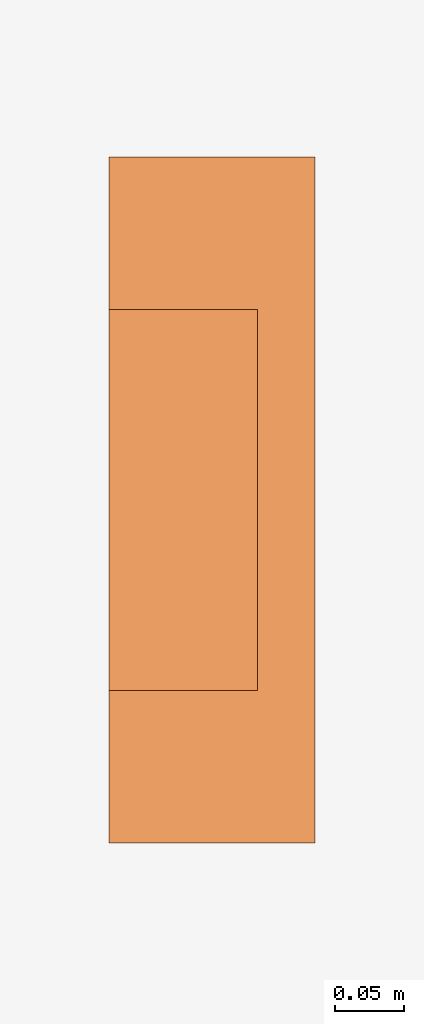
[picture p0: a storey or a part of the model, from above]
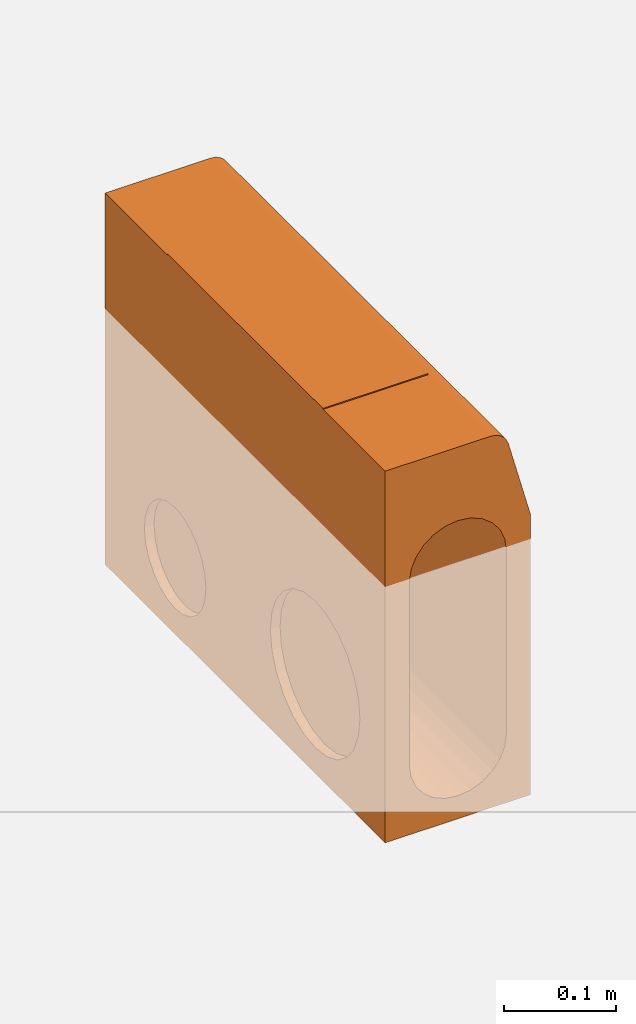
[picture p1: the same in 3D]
Properties of the parts of a building model (IFC2X3)

# File
Description: ViewDefinition [CoordinationView]
File name: 4233 - Access Unit - 500mm LG.ifc
Time: 2013-09-02T12:40:25
Written by: Autodesk Revit 2013
Made in: 20120221_2030(x64)

# IfcProject, Project Number
LongName: Project Name; Phase: Project Status

# IfcSite, Default
RefLatitude: 42, 21, 30, 344238; RefLongitude: -71, -3, -35, -194702; RefElevation: 0 mm

# IfcBuilding
Pset_BuildingCommon - NumberOfStoreys: 1
Other - Project Address: ## Street City, State Zip; Project Name: Project Name; Project Issue Date: Issue Date; Project Status: Project Status; Project Number: Project Number; Client Name: Owner

# IfcBuildingStorey, Level 1
LongName: Level 1; Elevation: 0 mm
Constraints - Elevation Base: 0; Elevation: 0 mm
Graphics - Line Pattern: Center; Symbol: M_Level Head - Circle: M_Level Head - Circle; Symbol at End 1 Default: no; Line Weight: 1; Symbol at End 2 Default: yes; Color: 0
Dimensions - Computation Height: 0 mm
Identity Data - Name: Level 1; Structural: no; Building Story: yes

# IfcBuildingElementProxy: 4233 - Access Unit - 500mm LG, Civil-Drainage-Channel-ACO-KerbDrain-HB405:4233 - Access Unit - 500mm LG:4233 - Access Unit - 500mm LG:312781
In: Level 1
Material: ACO Polymer Concrete., Iron, Cast
Constraints - Level: Level: Level 1; Moves With Nearby Elements: no
Dimensions - Volume: 15157016 mm3; Circular Void Depth: 2000 mm; Void Width: 150 mm; Void Length: 500 mm; Void Depth: -280 mm
Phasing - Phase Created: New Construction
Pset_BuildingElementProxyCommon - Reference: 4233 - Access Unit - 500mm LG
Construction - RH inlet/outlet end cap: no; HB405 - 500: no; RH drop kerb: no; HB405 500_blindunit: no; Closing end cap: no; HB405 - 1000: no; Centre Stone: no; Access Unit: yes; LH drop kerb: no; LH inlet/outlet end cap: no
Materials and Finishes - Connection Pipe Material Colour: N/A; End Cap Material: N/A; Access Cover/Frame Material: Ductile Iron; Channel Colour: Grey; Access Cover/Frame Finish: Water Based Paint Coating; Channel Material: Vienite® Synthetic Resin Concrete; End Cap Colour: N/A; Access Cover/Frame Colour: Black; Connection Pipe Material: N/A
Identity Data - Telephone: +44 (0)1462 816666; OmniClass Title: Rainwater Removal; Model: ACO KerbDrain HB405; Price: POA - contact ACO; OmniClass Number: 23.70.50.24; Installation guidelines: http://www.aco.co.uk/download.php?id=120; e-mail Technical: technical@aco.co.uk; Address: ACO Business Park, Hitchin Road, Shefford, Bedfordshire, United Kingdom SG17 5TE; Maintenance guidelines: http://www.aco.co.uk/download.php?id=120; Cost: 0; Assembly Description: Rain Water Drainage; Assembly Code: D2040; Manufacturer: ACO Technologies plc - ACO Water Management Division; URL: www.aco.co.uk; Product brochure: http://www.aco.co.uk/download.php?id=120; Model Description: Combined kerb and drainage system; Product Code: 4233; Type Comments: ACO KerbDrain HB405 half battered access unit 500mm long; Product Page URL: http://www.aco.co.uk/product_detail.php?id=3; e-mail Sales: customersupport@aco.co.uk; Fax: +44 (0)1462 815895
Data - Channel C.S.A: 0.03m²; ACO Hydraulic Design Software: http://www.acodesign.co.uk; Concrete Surround Volume - Load Class A 15 - D 400 - Grass or Asphalt Pavement: 0.16m³/m; Hydraulic Performance: http://www.aco.co.uk/download.php?id=120; Product Weight: 34.3 Kg; Load Class: A 15 - D 400; Drainage Slot Width: N/A; Product Dimensions: 500mm x 150mm x 405mm (LxWxH); Invert Depth: 380mm; Concrete Surround Volume - Load Class A 15 - D 400 - Concrete Pavement: 0.17m³/m; Connection Pipe O.D: N/A; Product Standard: BS EN 1433:2002, CE marked, Kitemarked; Installation - Concrete Grade: Refer to brochure; Drainage Slot Intake area: N/A
General - SerialNumber: 0.000000; TagNumber: 0.000000
Green Building Properties - End Cap Recycled Material Content: N/A; Channel Recyclable: Fully recyclable; End Cap Recyclable: N/A; Access Cover/Frame Recyclable: Fully recyclable; Channel Recycled Material Content: 20% minimum; Access Cover/Frame Recycled Material Content: Between 40% - 90%
Other - Revision: 1; CreatedBy: www.aco.co.uk

# IfcOpeningElement: Recess (2)
In: Level 1
Constraints - Level: Level: Level 1; Related to Mass: no; Room Bounding: yes; Height Offset From Level: 0 mm
Structural - Structural: no; Enable Analytical Model: no
Dimensions - Thickness: 400 mm; Perimeter: 51360 mm; Area: 151470000 mm2; Volume: 60567000000 mm3
Phasing - Phase Created: New Construction
Analytical Properties - Absorptance: 0.1; Roughness: 1
Construction - Function: 0; Default Thickness: 400 mm
Materials and Finishes - Structural Material: Plant
Graphics - Coarse Scale Fill Color: 0

# IfcSlab: Floor:Generic Floor - 400mm, Floor:Generic Floor - 400mm:193825
In: Level 1
PredefinedType: FLOOR; Material: Plant 400 mm
Constraints - Level: Level: Level 1; Related to Mass: no; Room Bounding: yes; Height Offset From Level: 0 mm
Structural - Structural: no; Enable Analytical Model: no
Dimensions - Thickness: 400 mm; Perimeter: 51360 mm; Area: 151470000 mm2; Volume: 60567000000 mm3
Phasing - Phase Created: New Construction
Pset_SlabCommon - Reference: Generic Floor - 400mm; IsExternal: no; LoadBearing: yes
Analytical Properties - Absorptance: 0.1; Roughness: 1
Construction - Function: 0; Default Thickness: 400 mm
Materials and Finishes - Structural Material: Plant
Graphics - Coarse Scale Fill Color: 0
